VERSION 5.7 ;
  NOWIREEXTENSIONATPIN ON ;
  DIVIDERCHAR "/" ;
  BUSBITCHARS "[]" ;
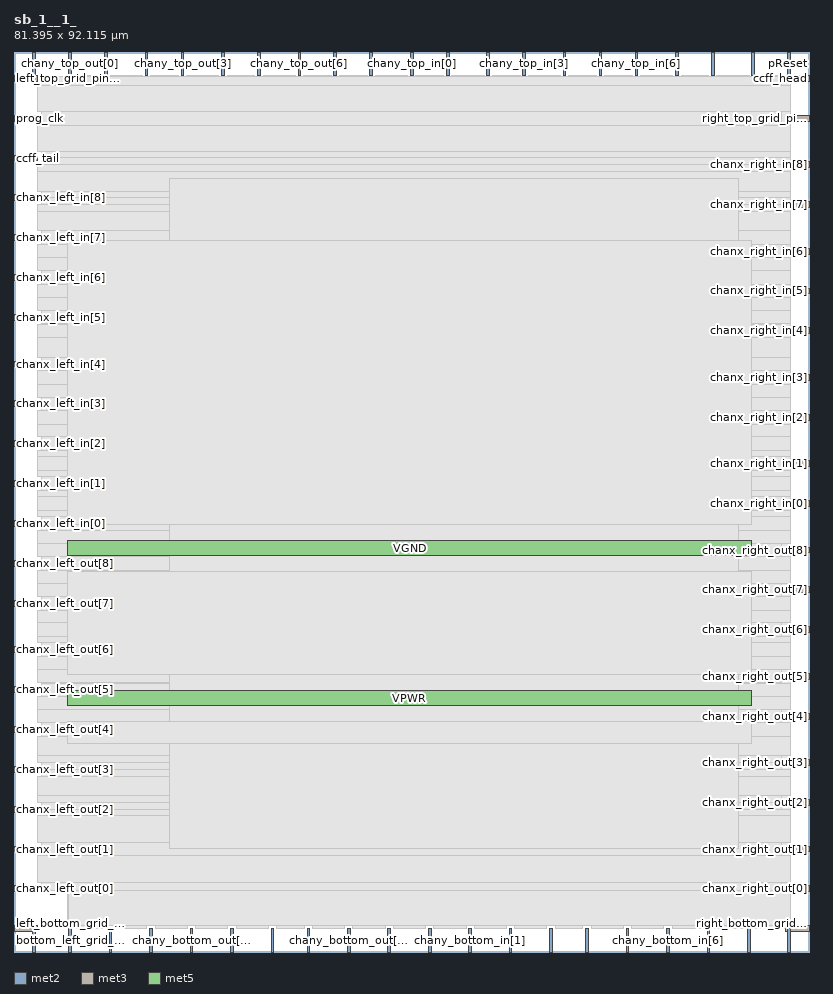
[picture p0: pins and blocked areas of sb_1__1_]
MACRO sb_1__1_
  CLASS BLOCK ;
  FOREIGN sb_1__1_ ;
  ORIGIN 0.000 0.000 ;
  SIZE 81.395 BY 92.115 ;
  PIN bottom_left_grid_pin_13_
    DIRECTION INPUT ;
    PORT
      LAYER met2 ;
        RECT 1.930 0.000 2.210 2.400 ;
    END
  END bottom_left_grid_pin_13_
  PIN bottom_right_grid_pin_11_
    DIRECTION INPUT ;
    PORT
      LAYER met2 ;
        RECT 79.210 0.000 79.490 2.400 ;
    END
  END bottom_right_grid_pin_11_
  PIN ccff_head
    DIRECTION INPUT ;
    PORT
      LAYER met3 ;
        RECT 78.995 89.120 81.395 89.720 ;
    END
  END ccff_head
  PIN ccff_tail
    DIRECTION OUTPUT TRISTATE ;
    PORT
      LAYER met3 ;
        RECT 0.000 80.960 2.400 81.560 ;
    END
  END ccff_tail
  PIN chanx_left_in[0]
    DIRECTION INPUT ;
    PORT
      LAYER met3 ;
        RECT 0.000 43.560 2.400 44.160 ;
    END
  END chanx_left_in[0]
  PIN chanx_left_in[1]
    DIRECTION INPUT ;
    PORT
      LAYER met3 ;
        RECT 0.000 47.640 2.400 48.240 ;
    END
  END chanx_left_in[1]
  PIN chanx_left_in[2]
    DIRECTION INPUT ;
    PORT
      LAYER met3 ;
        RECT 0.000 51.720 2.400 52.320 ;
    END
  END chanx_left_in[2]
  PIN chanx_left_in[3]
    DIRECTION INPUT ;
    PORT
      LAYER met3 ;
        RECT 0.000 55.800 2.400 56.400 ;
    END
  END chanx_left_in[3]
  PIN chanx_left_in[4]
    DIRECTION INPUT ;
    PORT
      LAYER met3 ;
        RECT 0.000 59.880 2.400 60.480 ;
    END
  END chanx_left_in[4]
  PIN chanx_left_in[5]
    DIRECTION INPUT ;
    PORT
      LAYER met3 ;
        RECT 0.000 64.640 2.400 65.240 ;
    END
  END chanx_left_in[5]
  PIN chanx_left_in[6]
    DIRECTION INPUT ;
    PORT
      LAYER met3 ;
        RECT 0.000 68.720 2.400 69.320 ;
    END
  END chanx_left_in[6]
  PIN chanx_left_in[7]
    DIRECTION INPUT ;
    PORT
      LAYER met3 ;
        RECT 0.000 72.800 2.400 73.400 ;
    END
  END chanx_left_in[7]
  PIN chanx_left_in[8]
    DIRECTION INPUT ;
    PORT
      LAYER met3 ;
        RECT 0.000 76.880 2.400 77.480 ;
    END
  END chanx_left_in[8]
  PIN chanx_left_out[0]
    DIRECTION OUTPUT TRISTATE ;
    PORT
      LAYER met3 ;
        RECT 0.000 6.160 2.400 6.760 ;
    END
  END chanx_left_out[0]
  PIN chanx_left_out[1]
    DIRECTION OUTPUT TRISTATE ;
    PORT
      LAYER met3 ;
        RECT 0.000 10.240 2.400 10.840 ;
    END
  END chanx_left_out[1]
  PIN chanx_left_out[2]
    DIRECTION OUTPUT TRISTATE ;
    PORT
      LAYER met3 ;
        RECT 0.000 14.320 2.400 14.920 ;
    END
  END chanx_left_out[2]
  PIN chanx_left_out[3]
    DIRECTION OUTPUT TRISTATE ;
    PORT
      LAYER met3 ;
        RECT 0.000 18.400 2.400 19.000 ;
    END
  END chanx_left_out[3]
  PIN chanx_left_out[4]
    DIRECTION OUTPUT TRISTATE ;
    PORT
      LAYER met3 ;
        RECT 0.000 22.480 2.400 23.080 ;
    END
  END chanx_left_out[4]
  PIN chanx_left_out[5]
    DIRECTION OUTPUT TRISTATE ;
    PORT
      LAYER met3 ;
        RECT 0.000 26.560 2.400 27.160 ;
    END
  END chanx_left_out[5]
  PIN chanx_left_out[6]
    DIRECTION OUTPUT TRISTATE ;
    PORT
      LAYER met3 ;
        RECT 0.000 30.640 2.400 31.240 ;
    END
  END chanx_left_out[6]
  PIN chanx_left_out[7]
    DIRECTION OUTPUT TRISTATE ;
    PORT
      LAYER met3 ;
        RECT 0.000 35.400 2.400 36.000 ;
    END
  END chanx_left_out[7]
  PIN chanx_left_out[8]
    DIRECTION OUTPUT TRISTATE ;
    PORT
      LAYER met3 ;
        RECT 0.000 39.480 2.400 40.080 ;
    END
  END chanx_left_out[8]
  PIN chanx_right_in[0]
    DIRECTION INPUT ;
    PORT
      LAYER met3 ;
        RECT 78.995 45.600 81.395 46.200 ;
    END
  END chanx_right_in[0]
  PIN chanx_right_in[1]
    DIRECTION INPUT ;
    PORT
      LAYER met3 ;
        RECT 78.995 49.680 81.395 50.280 ;
    END
  END chanx_right_in[1]
  PIN chanx_right_in[2]
    DIRECTION INPUT ;
    PORT
      LAYER met3 ;
        RECT 78.995 54.440 81.395 55.040 ;
    END
  END chanx_right_in[2]
  PIN chanx_right_in[3]
    DIRECTION INPUT ;
    PORT
      LAYER met3 ;
        RECT 78.995 58.520 81.395 59.120 ;
    END
  END chanx_right_in[3]
  PIN chanx_right_in[4]
    DIRECTION INPUT ;
    PORT
      LAYER met3 ;
        RECT 78.995 63.280 81.395 63.880 ;
    END
  END chanx_right_in[4]
  PIN chanx_right_in[5]
    DIRECTION INPUT ;
    PORT
      LAYER met3 ;
        RECT 78.995 67.360 81.395 67.960 ;
    END
  END chanx_right_in[5]
  PIN chanx_right_in[6]
    DIRECTION INPUT ;
    PORT
      LAYER met3 ;
        RECT 78.995 71.440 81.395 72.040 ;
    END
  END chanx_right_in[6]
  PIN chanx_right_in[7]
    DIRECTION INPUT ;
    PORT
      LAYER met3 ;
        RECT 78.995 76.200 81.395 76.800 ;
    END
  END chanx_right_in[7]
  PIN chanx_right_in[8]
    DIRECTION INPUT ;
    PORT
      LAYER met3 ;
        RECT 78.995 80.280 81.395 80.880 ;
    END
  END chanx_right_in[8]
  PIN chanx_right_out[0]
    DIRECTION OUTPUT TRISTATE ;
    PORT
      LAYER met3 ;
        RECT 78.995 6.160 81.395 6.760 ;
    END
  END chanx_right_out[0]
  PIN chanx_right_out[1]
    DIRECTION OUTPUT TRISTATE ;
    PORT
      LAYER met3 ;
        RECT 78.995 10.240 81.395 10.840 ;
    END
  END chanx_right_out[1]
  PIN chanx_right_out[2]
    DIRECTION OUTPUT TRISTATE ;
    PORT
      LAYER met3 ;
        RECT 78.995 15.000 81.395 15.600 ;
    END
  END chanx_right_out[2]
  PIN chanx_right_out[3]
    DIRECTION OUTPUT TRISTATE ;
    PORT
      LAYER met3 ;
        RECT 78.995 19.080 81.395 19.680 ;
    END
  END chanx_right_out[3]
  PIN chanx_right_out[4]
    DIRECTION OUTPUT TRISTATE ;
    PORT
      LAYER met3 ;
        RECT 78.995 23.840 81.395 24.440 ;
    END
  END chanx_right_out[4]
  PIN chanx_right_out[5]
    DIRECTION OUTPUT TRISTATE ;
    PORT
      LAYER met3 ;
        RECT 78.995 27.920 81.395 28.520 ;
    END
  END chanx_right_out[5]
  PIN chanx_right_out[6]
    DIRECTION OUTPUT TRISTATE ;
    PORT
      LAYER met3 ;
        RECT 78.995 32.680 81.395 33.280 ;
    END
  END chanx_right_out[6]
  PIN chanx_right_out[7]
    DIRECTION OUTPUT TRISTATE ;
    PORT
      LAYER met3 ;
        RECT 78.995 36.760 81.395 37.360 ;
    END
  END chanx_right_out[7]
  PIN chanx_right_out[8]
    DIRECTION OUTPUT TRISTATE ;
    PORT
      LAYER met3 ;
        RECT 78.995 40.840 81.395 41.440 ;
    END
  END chanx_right_out[8]
  PIN chany_bottom_in[0]
    DIRECTION INPUT ;
    PORT
      LAYER met2 ;
        RECT 42.410 0.000 42.690 2.400 ;
    END
  END chany_bottom_in[0]
  PIN chany_bottom_in[1]
    DIRECTION INPUT ;
    PORT
      LAYER met2 ;
        RECT 46.550 0.000 46.830 2.400 ;
    END
  END chany_bottom_in[1]
  PIN chany_bottom_in[2]
    DIRECTION INPUT ;
    PORT
      LAYER met2 ;
        RECT 50.690 0.000 50.970 2.400 ;
    END
  END chany_bottom_in[2]
  PIN chany_bottom_in[3]
    DIRECTION INPUT ;
    PORT
      LAYER met2 ;
        RECT 54.830 0.000 55.110 2.400 ;
    END
  END chany_bottom_in[3]
  PIN chany_bottom_in[4]
    DIRECTION INPUT ;
    PORT
      LAYER met2 ;
        RECT 58.510 0.000 58.790 2.400 ;
    END
  END chany_bottom_in[4]
  PIN chany_bottom_in[5]
    DIRECTION INPUT ;
    PORT
      LAYER met2 ;
        RECT 62.650 0.000 62.930 2.400 ;
    END
  END chany_bottom_in[5]
  PIN chany_bottom_in[6]
    DIRECTION INPUT ;
    PORT
      LAYER met2 ;
        RECT 66.790 0.000 67.070 2.400 ;
    END
  END chany_bottom_in[6]
  PIN chany_bottom_in[7]
    DIRECTION INPUT ;
    PORT
      LAYER met2 ;
        RECT 70.930 0.000 71.210 2.400 ;
    END
  END chany_bottom_in[7]
  PIN chany_bottom_in[8]
    DIRECTION INPUT ;
    PORT
      LAYER met2 ;
        RECT 75.070 0.000 75.350 2.400 ;
    END
  END chany_bottom_in[8]
  PIN chany_bottom_out[0]
    DIRECTION OUTPUT TRISTATE ;
    PORT
      LAYER met2 ;
        RECT 5.610 0.000 5.890 2.400 ;
    END
  END chany_bottom_out[0]
  PIN chany_bottom_out[1]
    DIRECTION OUTPUT TRISTATE ;
    PORT
      LAYER met2 ;
        RECT 9.750 0.000 10.030 2.400 ;
    END
  END chany_bottom_out[1]
  PIN chany_bottom_out[2]
    DIRECTION OUTPUT TRISTATE ;
    PORT
      LAYER met2 ;
        RECT 13.890 0.000 14.170 2.400 ;
    END
  END chany_bottom_out[2]
  PIN chany_bottom_out[3]
    DIRECTION OUTPUT TRISTATE ;
    PORT
      LAYER met2 ;
        RECT 18.030 0.000 18.310 2.400 ;
    END
  END chany_bottom_out[3]
  PIN chany_bottom_out[4]
    DIRECTION OUTPUT TRISTATE ;
    PORT
      LAYER met2 ;
        RECT 22.170 0.000 22.450 2.400 ;
    END
  END chany_bottom_out[4]
  PIN chany_bottom_out[5]
    DIRECTION OUTPUT TRISTATE ;
    PORT
      LAYER met2 ;
        RECT 26.310 0.000 26.590 2.400 ;
    END
  END chany_bottom_out[5]
  PIN chany_bottom_out[6]
    DIRECTION OUTPUT TRISTATE ;
    PORT
      LAYER met2 ;
        RECT 29.990 0.000 30.270 2.400 ;
    END
  END chany_bottom_out[6]
  PIN chany_bottom_out[7]
    DIRECTION OUTPUT TRISTATE ;
    PORT
      LAYER met2 ;
        RECT 34.130 0.000 34.410 2.400 ;
    END
  END chany_bottom_out[7]
  PIN chany_bottom_out[8]
    DIRECTION OUTPUT TRISTATE ;
    PORT
      LAYER met2 ;
        RECT 38.270 0.000 38.550 2.400 ;
    END
  END chany_bottom_out[8]
  PIN chany_top_in[0]
    DIRECTION INPUT ;
    PORT
      LAYER met2 ;
        RECT 40.570 89.715 40.850 92.115 ;
    END
  END chany_top_in[0]
  PIN chany_top_in[1]
    DIRECTION INPUT ;
    PORT
      LAYER met2 ;
        RECT 44.250 89.715 44.530 92.115 ;
    END
  END chany_top_in[1]
  PIN chany_top_in[2]
    DIRECTION INPUT ;
    PORT
      LAYER met2 ;
        RECT 48.390 89.715 48.670 92.115 ;
    END
  END chany_top_in[2]
  PIN chany_top_in[3]
    DIRECTION INPUT ;
    PORT
      LAYER met2 ;
        RECT 52.070 89.715 52.350 92.115 ;
    END
  END chany_top_in[3]
  PIN chany_top_in[4]
    DIRECTION INPUT ;
    PORT
      LAYER met2 ;
        RECT 56.210 89.715 56.490 92.115 ;
    END
  END chany_top_in[4]
  PIN chany_top_in[5]
    DIRECTION INPUT ;
    PORT
      LAYER met2 ;
        RECT 59.890 89.715 60.170 92.115 ;
    END
  END chany_top_in[5]
  PIN chany_top_in[6]
    DIRECTION INPUT ;
    PORT
      LAYER met2 ;
        RECT 63.570 89.715 63.850 92.115 ;
    END
  END chany_top_in[6]
  PIN chany_top_in[7]
    DIRECTION INPUT ;
    PORT
      LAYER met2 ;
        RECT 67.710 89.715 67.990 92.115 ;
    END
  END chany_top_in[7]
  PIN chany_top_in[8]
    DIRECTION INPUT ;
    PORT
      LAYER met2 ;
        RECT 71.390 89.715 71.670 92.115 ;
    END
  END chany_top_in[8]
  PIN chany_top_out[0]
    DIRECTION OUTPUT TRISTATE ;
    PORT
      LAYER met2 ;
        RECT 5.610 89.715 5.890 92.115 ;
    END
  END chany_top_out[0]
  PIN chany_top_out[1]
    DIRECTION OUTPUT TRISTATE ;
    PORT
      LAYER met2 ;
        RECT 9.290 89.715 9.570 92.115 ;
    END
  END chany_top_out[1]
  PIN chany_top_out[2]
    DIRECTION OUTPUT TRISTATE ;
    PORT
      LAYER met2 ;
        RECT 13.430 89.715 13.710 92.115 ;
    END
  END chany_top_out[2]
  PIN chany_top_out[3]
    DIRECTION OUTPUT TRISTATE ;
    PORT
      LAYER met2 ;
        RECT 17.110 89.715 17.390 92.115 ;
    END
  END chany_top_out[3]
  PIN chany_top_out[4]
    DIRECTION OUTPUT TRISTATE ;
    PORT
      LAYER met2 ;
        RECT 21.250 89.715 21.530 92.115 ;
    END
  END chany_top_out[4]
  PIN chany_top_out[5]
    DIRECTION OUTPUT TRISTATE ;
    PORT
      LAYER met2 ;
        RECT 24.930 89.715 25.210 92.115 ;
    END
  END chany_top_out[5]
  PIN chany_top_out[6]
    DIRECTION OUTPUT TRISTATE ;
    PORT
      LAYER met2 ;
        RECT 29.070 89.715 29.350 92.115 ;
    END
  END chany_top_out[6]
  PIN chany_top_out[7]
    DIRECTION OUTPUT TRISTATE ;
    PORT
      LAYER met2 ;
        RECT 32.750 89.715 33.030 92.115 ;
    END
  END chany_top_out[7]
  PIN chany_top_out[8]
    DIRECTION OUTPUT TRISTATE ;
    PORT
      LAYER met2 ;
        RECT 36.430 89.715 36.710 92.115 ;
    END
  END chany_top_out[8]
  PIN left_bottom_grid_pin_12_
    DIRECTION INPUT ;
    PORT
      LAYER met3 ;
        RECT 0.000 2.080 2.400 2.680 ;
    END
  END left_bottom_grid_pin_12_
  PIN left_top_grid_pin_10_
    DIRECTION INPUT ;
    PORT
      LAYER met3 ;
        RECT 0.000 89.120 2.400 89.720 ;
    END
  END left_top_grid_pin_10_
  PIN pReset
    DIRECTION INPUT ;
    PORT
      LAYER met2 ;
        RECT 79.210 89.715 79.490 92.115 ;
    END
  END pReset
  PIN prog_clk
    DIRECTION INPUT ;
    PORT
      LAYER met3 ;
        RECT 0.000 85.040 2.400 85.640 ;
    END
  END prog_clk
  PIN right_bottom_grid_pin_12_
    DIRECTION INPUT ;
    PORT
      LAYER met3 ;
        RECT 78.995 2.080 81.395 2.680 ;
    END
  END right_bottom_grid_pin_12_
  PIN right_top_grid_pin_10_
    DIRECTION INPUT ;
    PORT
      LAYER met3 ;
        RECT 78.995 85.040 81.395 85.640 ;
    END
  END right_top_grid_pin_10_
  PIN top_left_grid_pin_13_
    DIRECTION INPUT ;
    PORT
      LAYER met2 ;
        RECT 1.930 89.715 2.210 92.115 ;
    END
  END top_left_grid_pin_13_
  PIN top_right_grid_pin_11_
    DIRECTION INPUT ;
    PORT
      LAYER met2 ;
        RECT 75.530 89.715 75.810 92.115 ;
    END
  END top_right_grid_pin_11_
  PIN VPWR
    DIRECTION INPUT ;
    USE POWER ;
    PORT
      LAYER met5 ;
        RECT 5.520 25.195 75.440 26.795 ;
    END
  END VPWR
  PIN VGND
    DIRECTION INPUT ;
    USE GROUND ;
    PORT
      LAYER met5 ;
        RECT 5.520 40.545 75.440 42.145 ;
    END
  END VGND
  OBS
      LAYER li1 ;
        RECT 5.520 10.795 75.440 78.965 ;
      LAYER met1 ;
        RECT 5.520 2.760 77.210 84.620 ;
      LAYER met2 ;
        RECT 6.170 89.435 9.010 89.715 ;
        RECT 9.850 89.435 13.150 89.715 ;
        RECT 13.990 89.435 16.830 89.715 ;
        RECT 17.670 89.435 20.970 89.715 ;
        RECT 21.810 89.435 24.650 89.715 ;
        RECT 25.490 89.435 28.790 89.715 ;
        RECT 29.630 89.435 32.470 89.715 ;
        RECT 33.310 89.435 36.150 89.715 ;
        RECT 36.990 89.435 40.290 89.715 ;
        RECT 41.130 89.435 43.970 89.715 ;
        RECT 44.810 89.435 48.110 89.715 ;
        RECT 48.950 89.435 51.790 89.715 ;
        RECT 52.630 89.435 55.930 89.715 ;
        RECT 56.770 89.435 59.610 89.715 ;
        RECT 60.450 89.435 63.290 89.715 ;
        RECT 64.130 89.435 67.430 89.715 ;
        RECT 68.270 89.435 71.110 89.715 ;
        RECT 71.950 89.435 75.250 89.715 ;
        RECT 76.090 89.435 78.930 89.715 ;
        RECT 5.610 2.680 79.490 89.435 ;
        RECT 6.170 2.400 9.470 2.680 ;
        RECT 10.310 2.400 13.610 2.680 ;
        RECT 14.450 2.400 17.750 2.680 ;
        RECT 18.590 2.400 21.890 2.680 ;
        RECT 22.730 2.400 26.030 2.680 ;
        RECT 26.870 2.400 29.710 2.680 ;
        RECT 30.550 2.400 33.850 2.680 ;
        RECT 34.690 2.400 37.990 2.680 ;
        RECT 38.830 2.400 42.130 2.680 ;
        RECT 42.970 2.400 46.270 2.680 ;
        RECT 47.110 2.400 50.410 2.680 ;
        RECT 51.250 2.400 54.550 2.680 ;
        RECT 55.390 2.400 58.230 2.680 ;
        RECT 59.070 2.400 62.370 2.680 ;
        RECT 63.210 2.400 66.510 2.680 ;
        RECT 67.350 2.400 70.650 2.680 ;
        RECT 71.490 2.400 74.790 2.680 ;
        RECT 75.630 2.400 78.930 2.680 ;
      LAYER met3 ;
        RECT 2.800 88.720 78.595 89.585 ;
        RECT 2.400 86.040 79.515 88.720 ;
        RECT 2.800 84.640 78.595 86.040 ;
        RECT 2.400 81.960 79.515 84.640 ;
        RECT 2.800 81.280 79.515 81.960 ;
        RECT 2.800 80.560 78.595 81.280 ;
        RECT 2.400 79.880 78.595 80.560 ;
        RECT 2.400 77.880 79.515 79.880 ;
        RECT 2.800 77.200 79.515 77.880 ;
        RECT 2.800 76.480 78.595 77.200 ;
        RECT 2.400 75.800 78.595 76.480 ;
        RECT 2.400 73.800 79.515 75.800 ;
        RECT 2.800 72.440 79.515 73.800 ;
        RECT 2.800 72.400 78.595 72.440 ;
        RECT 2.400 71.040 78.595 72.400 ;
        RECT 2.400 69.720 79.515 71.040 ;
        RECT 2.800 68.360 79.515 69.720 ;
        RECT 2.800 68.320 78.595 68.360 ;
        RECT 2.400 66.960 78.595 68.320 ;
        RECT 2.400 65.640 79.515 66.960 ;
        RECT 2.800 64.280 79.515 65.640 ;
        RECT 2.800 64.240 78.595 64.280 ;
        RECT 2.400 62.880 78.595 64.240 ;
        RECT 2.400 60.880 79.515 62.880 ;
        RECT 2.800 59.520 79.515 60.880 ;
        RECT 2.800 59.480 78.595 59.520 ;
        RECT 2.400 58.120 78.595 59.480 ;
        RECT 2.400 56.800 79.515 58.120 ;
        RECT 2.800 55.440 79.515 56.800 ;
        RECT 2.800 55.400 78.595 55.440 ;
        RECT 2.400 54.040 78.595 55.400 ;
        RECT 2.400 52.720 79.515 54.040 ;
        RECT 2.800 51.320 79.515 52.720 ;
        RECT 2.400 50.680 79.515 51.320 ;
        RECT 2.400 49.280 78.595 50.680 ;
        RECT 2.400 48.640 79.515 49.280 ;
        RECT 2.800 47.240 79.515 48.640 ;
        RECT 2.400 46.600 79.515 47.240 ;
        RECT 2.400 45.200 78.595 46.600 ;
        RECT 2.400 44.560 79.515 45.200 ;
        RECT 2.800 43.160 79.515 44.560 ;
        RECT 2.400 41.840 79.515 43.160 ;
        RECT 2.400 40.480 78.595 41.840 ;
        RECT 2.800 40.440 78.595 40.480 ;
        RECT 2.800 39.080 79.515 40.440 ;
        RECT 2.400 37.760 79.515 39.080 ;
        RECT 2.400 36.400 78.595 37.760 ;
        RECT 2.800 36.360 78.595 36.400 ;
        RECT 2.800 35.000 79.515 36.360 ;
        RECT 2.400 33.680 79.515 35.000 ;
        RECT 2.400 32.280 78.595 33.680 ;
        RECT 2.400 31.640 79.515 32.280 ;
        RECT 2.800 30.240 79.515 31.640 ;
        RECT 2.400 28.920 79.515 30.240 ;
        RECT 2.400 27.560 78.595 28.920 ;
        RECT 2.800 27.520 78.595 27.560 ;
        RECT 2.800 26.160 79.515 27.520 ;
        RECT 2.400 24.840 79.515 26.160 ;
        RECT 2.400 23.480 78.595 24.840 ;
        RECT 2.800 23.440 78.595 23.480 ;
        RECT 2.800 22.080 79.515 23.440 ;
        RECT 2.400 20.080 79.515 22.080 ;
        RECT 2.400 19.400 78.595 20.080 ;
        RECT 2.800 18.680 78.595 19.400 ;
        RECT 2.800 18.000 79.515 18.680 ;
        RECT 2.400 16.000 79.515 18.000 ;
        RECT 2.400 15.320 78.595 16.000 ;
        RECT 2.800 14.600 78.595 15.320 ;
        RECT 2.800 13.920 79.515 14.600 ;
        RECT 2.400 11.240 79.515 13.920 ;
        RECT 2.800 9.840 78.595 11.240 ;
        RECT 2.400 7.160 79.515 9.840 ;
        RECT 2.800 6.295 78.595 7.160 ;
      LAYER met4 ;
        RECT 15.935 10.640 74.150 79.120 ;
      LAYER met5 ;
        RECT 5.520 43.745 75.440 72.850 ;
        RECT 5.520 28.395 75.440 38.945 ;
        RECT 5.520 21.300 75.440 23.595 ;
  END
END sb_1__1_
END LIBRARY

